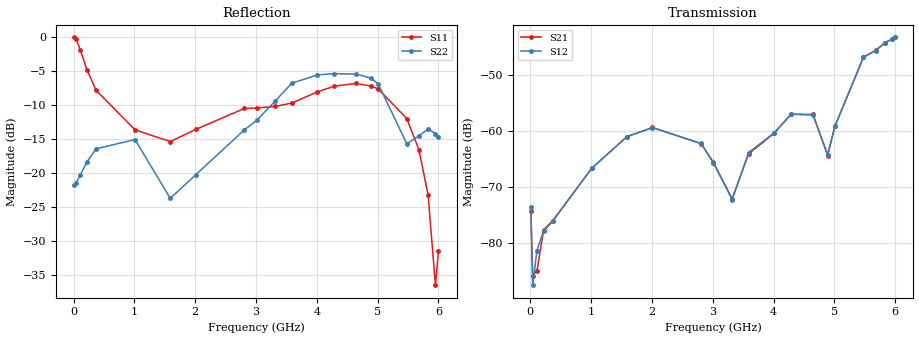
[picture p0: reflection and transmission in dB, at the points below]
!Agilent Technologies,N5230A,MY45001650,A.07.50.48
!Agilent N5230A: A.07.50.48
!Date: Saturday, July 08, 2017 15:59:50
!Correction: S11(Full 2 Port(1,2))
!S21(Full 2 Port(1,2))
!S12(Full 2 Port(1,2))
!S22(Full 2 Port(1,2))
!S2P File: Measurements: S11, S21, S12, S22:
# Hz S  dB  R 50
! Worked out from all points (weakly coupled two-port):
!   600 points, 10 MHz to 6 GHz, reference 50 ohm
!   highest |S21| = -43.28 dB at 6 GHz (marker M1); lowest = -85.8 dB at 40 MHz (marker M2)
!   lowest |S11| = -36.5 dB at 5.95 GHz (marker M3), VSWR 1.03, Z = 48.6 - j0.517 ohm
!   |S11| at or under -10 dB: 544.9 MHz to 3.502 GHz (2.957 GHz wide, 146 % of centre); 5.331 GHz to end of sweep
!   |S22| runs from -24.1 to -5.3 dB; largest |S21 - S12| = 0.00027
!   S11 on the Smith chart (normalised r, x): 10 MHz: 2, -19; 110 MHz: 0.49, -1.80; 370 MHz: 0.53, -0.43; 2.81 GHz: 0.59, +0.25; 4.29 GHz: 2.40, +0.51; 6 GHz: 0.97, +0.04
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1e7  -0.11 -6.0  -74.25 169.3  -73.60 84.5  -21.89 -7.9
4e7  -0.36 -22.5  -85.78 144.9  -87.49 76.1  -21.54 -14.1
1.1e8  -1.94 -55.4  -84.93 79.0  -81.34 58.2  -20.32 -37.6
2.2e8  -4.88 -90.6  -77.65 48.7  -77.80 43.4  -18.42 -66.9
3.7e8  -7.89 -121.7  -75.97 54.4  -76.10 58.4  -16.49 -93.5
1.01e9  -13.70 176.2  -66.66 63.6  -66.63 63.3  -15.14 -164.1
1.59e9  -15.43 168.6  -61.00 33.3  -60.97 33.7  -23.78 170.9
2.01e9  -13.64 172.0  -59.35 6.3  -59.38 5.9  -20.30 172.2
2.81e9  -10.56 139.9  -62.25 -57.7  -62.21 -57.8  -13.69 164.1
3.01e9  -10.49 124.0  -65.62 -77.9  -65.55 -77.6  -12.32 158.3
3.32e9  -10.26 97.2  -72.06 159.4  -72.21 158.2  -9.43 158.8
3.59e9  -9.76 68.7  -64.06 59.2  -63.84 59.7  -6.84 148.9
4.01e9  -8.12 29.5  -60.39 27.0  -60.32 27.4  -5.63 126.6
4.29e9  -7.27 11.4  -56.99 6.0  -56.96 6.2  -5.44 113.0
4.65e9  -6.87 -7.8  -57.03 -34.3  -57.14 -34.6  -5.51 85.3
4.89e9  -7.27 -17.9  -64.36 -15.2  -64.18 -14.1  -6.10 60.2
5.01e9  -7.69 -22.7  -59.12 17.5  -59.16 16.9  -6.96 46.4
5.48e9  -12.07 -44.9  -46.78 -20.5  -46.83 -20.5  -15.77 27.4
5.68e9  -16.66 -56.3  -45.61 -41.7  -45.62 -41.6  -14.58 39.3
5.83e9  -23.28 -69.2  -44.21 -56.1  -44.23 -56.1  -13.58 28.8
5.95e9  -36.54 -159.1  -43.58 -66.8  -43.60 -66.6  -14.25 18.3
6e9  -31.56 122.0  -43.28 -70.9  -43.27 -70.9  -14.69 14.1
